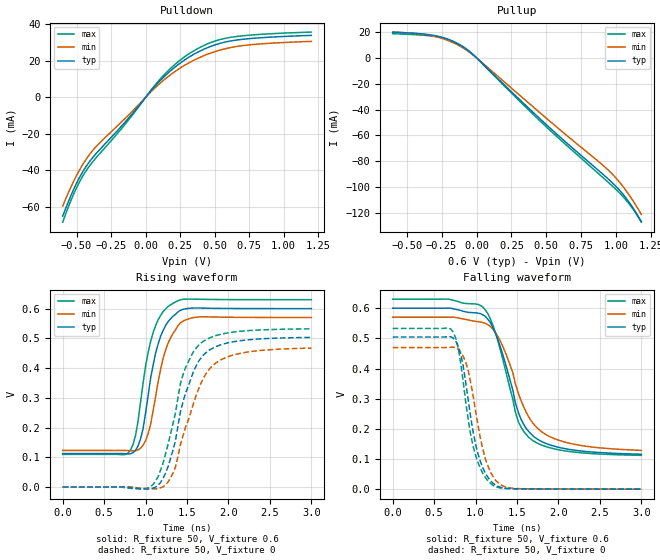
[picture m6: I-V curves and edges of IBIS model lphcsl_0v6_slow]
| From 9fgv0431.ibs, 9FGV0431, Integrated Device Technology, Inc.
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[Model]   lphcsl_0v6_slow
Model_type Output
Polarity Non-Inverting
Enable Active-High
Vmeas = 0.4000V
Cref = 2.0000pF
Rref = 0
Vref = 0.4000V
C_comp 1.1000pF 1.0000pF 1.2000pF
[Temperature Range] 25 75 0
[Voltage Range] 0.6000V 0.5700V 0.6300V
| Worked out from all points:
|   slope of the pulldown table from 0 to 0.09 V, typ, clamps not added: 11.3 ohm
|   slope of the pullup table from 0 to 0.09 V, typ, clamps not added: 9.48 ohm
|   rising waveform, R_fixture 50, V_fixture 0.6: 20-80 % time 199ps typ, 206ps min, 195ps max; typ from 0.113 V to 0.6 V
|   rising waveform, R_fixture 50, V_fixture 0: 20-80 % time 296ps typ, 331ps min, 287ps max; typ from 0 V to 0.503 V
|   falling waveform, R_fixture 50, V_fixture 0.6: 20-80 % time 326ps typ, 384ps min, 300ps max; typ from 0.6 V to 0.116 V
|   falling waveform, R_fixture 50, V_fixture 0: 20-80 % time 195ps typ, 202ps min, 192ps max; typ from 0.504 V to 0 V
[Pulldown]
|Voltage I(typ) I(min) I(max)
-600mV    -65.21mA   -59.64mA   -68.48mA
-540mV    -53.77mA   -49.11mA   -56.45mA
-500mV    -47.15mA   -42.93mA   -49.62mA
-440mV    -38.96mA   -35.03mA   -41.34mA
-380mV    -32.74mA   -28.88mA   -35.09mA
-140mV    -12.81mA   -10.93mA   -13.94mA
100mV     8.769mA    7.433mA    9.577mA
260mV     19.34mA    16.56mA    21mA
420mV     26.34mA    22.82mA    28.41mA
580mV     30.41mA    26.74mA    32.45mA
800mV     32.55mA    29.15mA    34.41mA
1.2V      34.02mA    30.72mA    35.83mA
[Pullup]
|Voltage I(typ) I(min) I(max)
-600mV    19.81mA    19.9mA     18.63mA
-380mV    18.39mA    18.13mA    17.44mA
-260mV    16.25mA    15.47mA    15.78mA
-160mV    12.32mA    11.36mA    12.3mA
-60mV     5.642mA    5.048mA    5.78mA
0V        720.8pA    1.104nA    645pA
480mV     -49.7mA    -44.85mA   -51.38mA
940mV     -93.39mA   -86.48mA   -95.95mA
1V        -99.57mA   -93.12mA   -101.9mA
1.06V     -107mA     -101.1mA   -108.6mA
1.12V     -116mA     -110.5mA   -116.9mA
1.18V     -126.7mA   -121.1mA   -127.1mA
[Ramp]
| variable typ min max
dV/dt_r 0.3017/0.3160n 0.2800/0.3389n 0.3190/0.3071n
dV/dt_f 0.2905/0.3464n 0.2648/0.4039n 0.3107/0.3200n
R_load = 50
[Rising Waveform]
R_fixture= 50
V_fixture= 0.6
V_fixture_min= 0.57
V_fixture_max= 0.63
|time V(typ) V(min) V(max)
0s        112.6mV    123mV      109.7mV
820ps     111.9mV    122.2mV    125.1mV
880ps     124.2mV    122.2mV    174.9mV
940ps     162.2mV    131.1mV    287.5mV
1.06ns    364.7mV    209.7mV    488.6mV
1.18ns    505.9mV    393.6mV    576.4mV
1.3ns     565.3mV    500.7mV    612.6mV
1.42ns    594.6mV    552.1mV    629.8mV
1.58ns    602.2mV    570mV      632mV
3ns       600.1mV    570.1mV    630mV
[Rising Waveform]
R_fixture= 50
V_fixture= 0
V_fixture_min= 0
V_fixture_max= 0
|time V(typ) V(min) V(max)
0s        0V         0V         0V
1.09ns    -3.871mV   -6.154mV   8.187mV
1.21ns    28.55mV    413.1uV    79.77mV
1.33ns    123.2mV    46.45mV    212.5mV
1.42ns    252.6mV    142.5mV    346.7mV
1.48ns    314.1mV    199.3mV    400.5mV
1.7ns     444.6mV    367.1mV    490.7mV
1.85ns    472.4mV    417.7mV    509.5mV
2.06ns    488.6mV    444.1mV    521.2mV
3ns       502.9mV    466.7mV    531.7mV
[Falling Waveform]
R_fixture= 50
V_fixture= 0.6
V_fixture_min= 0.57
V_fixture_max= 0.63
|time V(typ) V(min) V(max)
0s        600mV      570mV      630mV
670ps     600.3mV    570.1mV    630.2mV
1.09ns    577.6mV    552.1mV    603.4mV
1.18ns    551.5mV    539.1mV    562.9mV
1.27ns    495.3mV    505.6mV    491.2mV
1.42ns    357.8mV    408.8mV    328.5mV
1.52ns    251.4mV    314.8mV    220.9mV
1.7ns     174.8mV    216.3mV    159.6mV
2.09ns    133.8mV    155.2mV    126.6mV
3ns       115.9mV    128.7mV    112.2mV
[Falling Waveform]
R_fixture= 50
V_fixture= 0
V_fixture_min= 0
V_fixture_max= 0
|time V(typ) V(min) V(max)
0s        504.4mV    469.5mV    532.8mV
730ps     501.1mV    470.9mV    520.3mV
790ps     473.6mV    463.9mV    468.8mV
820ps     449.2mV    455mV      418.4mV
910ps     298mV      395.1mV    234.1mV
970ps     190.3mV    310.2mV    143.9mV
1.09ns    69.97mV    130.9mV    51.15mV
1.21ns    20.11mV    42.35mV    12.74mV
1.48ns    1.492mV    2.259mV    1.252mV
3ns       109.5uV    165.3uV    86.38uV
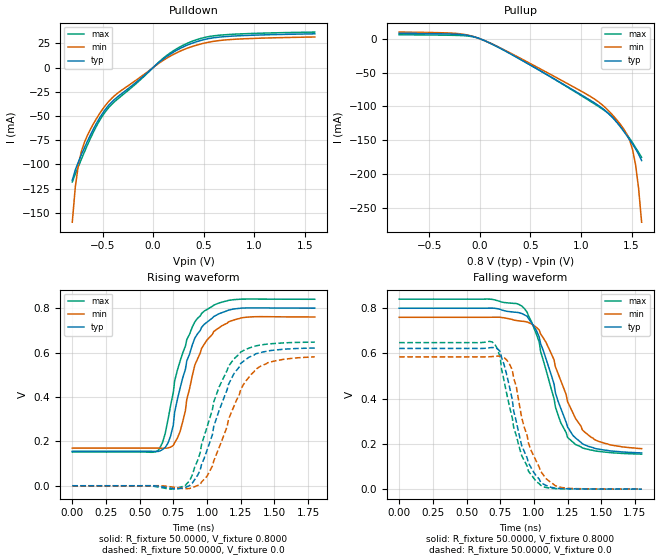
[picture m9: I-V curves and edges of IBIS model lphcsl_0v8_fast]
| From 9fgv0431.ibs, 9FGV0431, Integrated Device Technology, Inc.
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[Model]   lphcsl_0v8_fast
Model_type Output
Polarity   Non-Inverting
Enable   Active-High
Vmeas =  0.4000V
Cref =   2.0000pF
Rref =   0.0
Vref =   0.4000V
C_comp   1.1000pF   1.0000pF   1.2000pF
[Temperature Range]   25.0000   75.0000   0.0
[Voltage Range]   0.8000V   0.7600V   0.8400V
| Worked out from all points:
|   slope of the pulldown table from 0 to 0.12 V, typ, clamps not added: 11.7 ohm
|   slope of the pullup table from 0 to 0.12 V, typ, clamps not added: 14.9 ohm
|   rising waveform, R_fixture 50.0000, V_fixture 0.8000: 20-80 % time 164ps typ, 165ps min, 175ps max; typ from 0.156 V to 0.8 V
|   rising waveform, R_fixture 50.0000, V_fixture 0.0: 20-80 % time 214ps typ, 227ps min, 209ps max; typ from 0 V to 0.62 V
|   falling waveform, R_fixture 50.0000, V_fixture 0.8000: 20-80 % time 204ps typ, 235ps min, 194ps max; typ from 0.8 V to 0.16 V
|   falling waveform, R_fixture 50.0000, V_fixture 0.0: 20-80 % time 154ps typ, 161ps min, 161ps max; typ from 0.622 V to 0 V
[Pulldown]
|Voltage   I(typ)   I(min)   I(max)
-800mV    -116.2mA   -159.6mA   -118.1mA
-770mV    -105.7mA   -123.3mA   -110mA
-740mV    -97.45mA   -100.6mA   -102.3mA
-710mV    -89.96mA   -86.62mA   -94.65mA
-680mV    -82.85mA   -77.23mA   -87.18mA
-590mV    -63.31mA   -57.9mA    -66.46mA
-500mV    -47.21mA   -42.99mA   -49.67mA
-350mV    -30.12mA   -26.35mA   -32.41mA
130mV     11.06mA    9.39mA     12.07mA
430mV     26.68mA    23.13mA    28.76mA
760mV     32.3mA     28.88mA    34.18mA
1.6V      34.82mA    31.54mA    36.61mA
[Pullup]
|Voltage   I(typ)   I(min)   I(max)
-800mV    8.048mA    9.895mA    5.936mA
-230mV    6.658mA    7.836mA    4.986mA
10mV      -610.1uA   -603.7uA   -546.5uA
400mV     -30.63mA   -28.86mA   -30.13mA
1.18V     -99.5mA    -94.17mA   -100.9mA
1.36V     -124.8mA   -121.1mA   -123.5mA
1.42V     -136.4mA   -133mA     -134.6mA
1.48V     -149.1mA   -149.7mA   -147.2mA
1.51V     -155.9mA   -163.7mA   -153.9mA
1.54V     -163mA     -186.3mA   -161mA
1.57V     -170.8mA   -221.5mA   -168.2mA
1.6V      -180.3mA   -271.5mA   -175.6mA
[Ramp]
| variable   typ   min   max
dV/dt_r  0.3722/0.2102n   0.3484/0.2225n   0.3882/0.2059n
dV/dt_f  0.3838/0.2045n   0.3484/0.2297n   0.4109/0.1930n
R_load = 50.0000
[Rising Waveform]
R_fixture= 50.0000
V_fixture= 0.8000
V_fixture_min= 0.7600
V_fixture_max= 0.8400
|time   V(typ)   V(min)   V(max)
0s        155.5mV    169.8mV    151.7mV
640ps     154.8mV    169.6mV    160.5mV
690ps     172.4mV    168.9mV    235.5mV
730ps     224.5mV    173.9mV    361.2mV
780ps     388.3mV    214.2mV    520.2mV
840ps     525mV      339.1mV    629.7mV
890ps     632.6mV    493.1mV    713.7mV
980ps     727.4mV    637.8mV    786.9mV
1.25ns    800.1mV    755.4mV    840.5mV
1.8ns     800.1mV    760.3mV    840.1mV
[Rising Waveform]
R_fixture= 50.0000
V_fixture= 0.0
V_fixture_min= 0.0
V_fixture_max= 0.0
|time   V(typ)   V(min)   V(max)
0s        0V         0V         0V
840ps     -7.875mV   -13.3mV    1.691mV
870ps     428.9uV    -12.26mV   21.72mV
930ps     46.97mV    1.22mV     112.8mV
1ns       159.6mV    42.69mV    264mV
1.09ns    338.9mV    172.3mV    444.6mV
1.2ns     504.5mV    357.9mV    571.2mV
1.27ns    560.3mV    455.3mV    609mV
1.38ns    597.3mV    532mV      632.3mV
1.8ns     620.4mV    580.6mV    647mV
[Falling Waveform]
R_fixture= 50.0000
V_fixture= 0.8000
V_fixture_min= 0.7600
V_fixture_max= 0.8400
|time   V(typ)   V(min)   V(max)
0s        800mV      760mV      840mV
670ps     800.5mV    760.1mV    840.4mV
910ps     776.8mV    742.7mV    809.8mV
950ps     764.6mV    739.3mV    782.5mV
1.04ns    672mV      703.5mV    649.4mV
1.16ns    426.5mV    541.2mV    363.6mV
1.25ns    275.5mV    387.4mV    228.9mV
1.36ns    200.6mV    262mV      182.3mV
1.45ns    180.7mV    219.5mV    169.8mV
1.8ns     160.4mV    179.3mV    155.1mV
[Falling Waveform]
R_fixture= 50.0000
V_fixture= 0.0
V_fixture_min= 0.0
V_fixture_max= 0.0
|time   V(typ)   V(min)   V(max)
0s        622.3mV    585.1mV    648mV
710ps     625.8mV    587.2mV    641.1mV
750ps     608.4mV    588.3mV    582.7mV
760ps     583.3mV    586.1mV    531.6mV
840ps     396mV      527.4mV    314.4mV
910ps     192.1mV    315.2mV    147.9mV
960ps     115.6mV    204.1mV    79.71mV
1.05ns    31.62mV    79.9mV     17.67mV
1.2ns     2.941mV    8.187mV    1.99mV
1.8ns     219.8uV    384.2uV    157.9uV
